VERSION 5.8 ;
BUSBITCHARS "[]" ;
DIVIDERCHAR "/" ;
UNITS
    DATABASE MICRONS 1000 ;
END UNITS

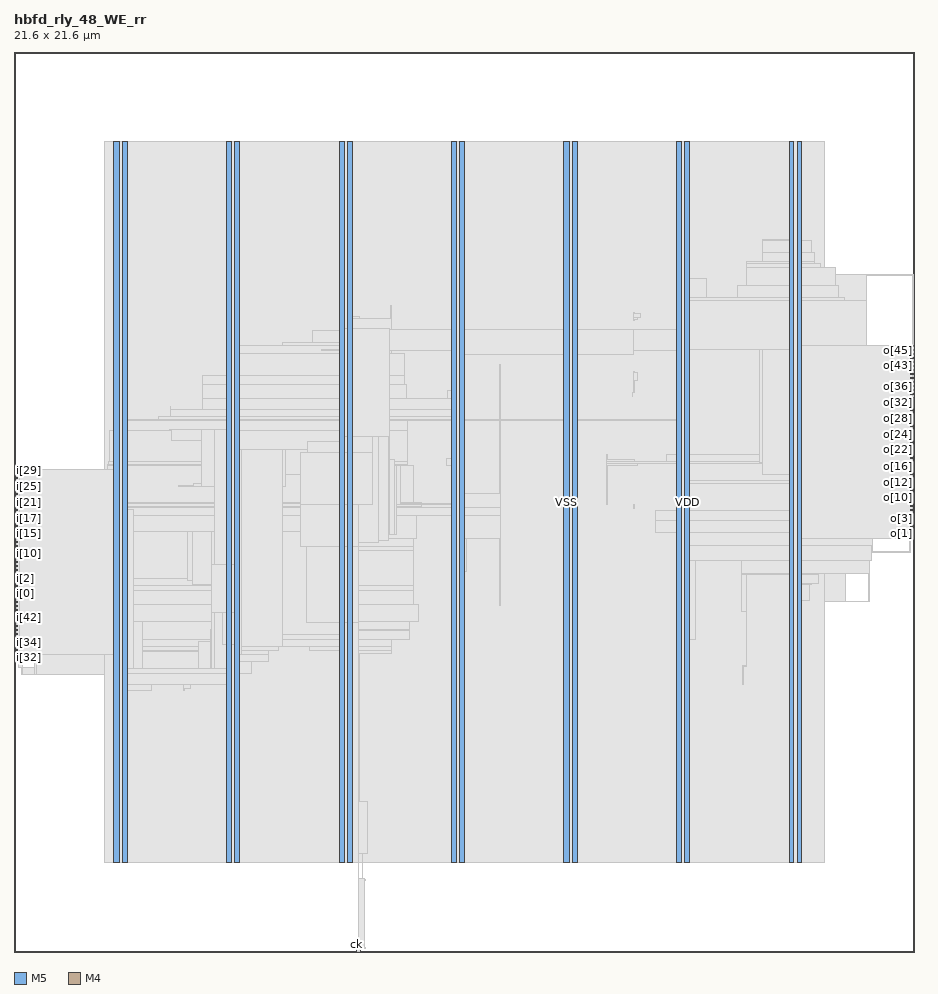
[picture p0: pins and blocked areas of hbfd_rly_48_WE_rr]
MACRO hbfd_rly_48_WE_rr
  FOREIGN hbfd_rly_48_WE_rr 0 0 ;
  CLASS BLOCK ;
  SIZE 21.6 BY 21.6 ;
  PIN ck
    DIRECTION INPUT ;
    USE SIGNAL ;
    PORT
      LAYER M5 ;
        RECT  8.208 0 8.232 0.084 ;
    END
  END ck
  PIN i[0]
    DIRECTION INPUT ;
    USE SIGNAL ;
    PORT
      LAYER M4 ;
        RECT  0 8.592 0.084 8.616 ;
    END
  END i[0]
  PIN i[10]
    DIRECTION INPUT ;
    USE SIGNAL ;
    PORT
      LAYER M4 ;
        RECT  0 9.552 0.084 9.576 ;
    END
  END i[10]
  PIN i[11]
    DIRECTION INPUT ;
    USE SIGNAL ;
    PORT
      LAYER M4 ;
        RECT  0 9.648 0.084 9.672 ;
    END
  END i[11]
  PIN i[12]
    DIRECTION INPUT ;
    USE SIGNAL ;
    PORT
      LAYER M4 ;
        RECT  0 9.744 0.084 9.768 ;
    END
  END i[12]
  PIN i[13]
    DIRECTION INPUT ;
    USE SIGNAL ;
    PORT
      LAYER M4 ;
        RECT  0 9.84 0.084 9.864 ;
    END
  END i[13]
  PIN i[14]
    DIRECTION INPUT ;
    USE SIGNAL ;
    PORT
      LAYER M4 ;
        RECT  0 9.936 0.084 9.96 ;
    END
  END i[14]
  PIN i[15]
    DIRECTION INPUT ;
    USE SIGNAL ;
    PORT
      LAYER M4 ;
        RECT  0 10.032 0.084 10.056 ;
    END
  END i[15]
  PIN i[16]
    DIRECTION INPUT ;
    USE SIGNAL ;
    PORT
      LAYER M4 ;
        RECT  0 10.128 0.084 10.152 ;
    END
  END i[16]
  PIN i[17]
    DIRECTION INPUT ;
    USE SIGNAL ;
    PORT
      LAYER M4 ;
        RECT  0 10.224 0.084 10.248 ;
    END
  END i[17]
  PIN i[18]
    DIRECTION INPUT ;
    USE SIGNAL ;
    PORT
      LAYER M4 ;
        RECT  0 10.32 0.084 10.344 ;
    END
  END i[18]
  PIN i[19]
    DIRECTION INPUT ;
    USE SIGNAL ;
    PORT
      LAYER M4 ;
        RECT  0 10.416 0.084 10.44 ;
    END
  END i[19]
  PIN i[1]
    DIRECTION INPUT ;
    USE SIGNAL ;
    PORT
      LAYER M4 ;
        RECT  0 8.688 0.084 8.712 ;
    END
  END i[1]
  PIN i[20]
    DIRECTION INPUT ;
    USE SIGNAL ;
    PORT
      LAYER M4 ;
        RECT  0 10.512 0.084 10.536 ;
    END
  END i[20]
  PIN i[21]
    DIRECTION INPUT ;
    USE SIGNAL ;
    PORT
      LAYER M4 ;
        RECT  0 10.608 0.084 10.632 ;
    END
  END i[21]
  PIN i[22]
    DIRECTION INPUT ;
    USE SIGNAL ;
    PORT
      LAYER M4 ;
        RECT  0 10.704 0.084 10.728 ;
    END
  END i[22]
  PIN i[23]
    DIRECTION INPUT ;
    USE SIGNAL ;
    PORT
      LAYER M4 ;
        RECT  0 10.8 0.084 10.824 ;
    END
  END i[23]
  PIN i[24]
    DIRECTION INPUT ;
    USE SIGNAL ;
    PORT
      LAYER M4 ;
        RECT  0 10.896 0.084 10.92 ;
    END
  END i[24]
  PIN i[25]
    DIRECTION INPUT ;
    USE SIGNAL ;
    PORT
      LAYER M4 ;
        RECT  0 10.992 0.084 11.016 ;
    END
  END i[25]
  PIN i[26]
    DIRECTION INPUT ;
    USE SIGNAL ;
    PORT
      LAYER M4 ;
        RECT  0 11.088 0.084 11.112 ;
    END
  END i[26]
  PIN i[27]
    DIRECTION INPUT ;
    USE SIGNAL ;
    PORT
      LAYER M4 ;
        RECT  0 11.184 0.084 11.208 ;
    END
  END i[27]
  PIN i[28]
    DIRECTION INPUT ;
    USE SIGNAL ;
    PORT
      LAYER M4 ;
        RECT  0 11.28 0.084 11.304 ;
    END
  END i[28]
  PIN i[29]
    DIRECTION INPUT ;
    USE SIGNAL ;
    PORT
      LAYER M4 ;
        RECT  0 11.376 0.084 11.4 ;
    END
  END i[29]
  PIN i[2]
    DIRECTION INPUT ;
    USE SIGNAL ;
    PORT
      LAYER M4 ;
        RECT  0 8.784 0.084 8.808 ;
    END
  END i[2]
  PIN i[30]
    DIRECTION INPUT ;
    USE SIGNAL ;
    PORT
      LAYER M4 ;
        RECT  0 11.472 0.084 11.496 ;
    END
  END i[30]
  PIN i[31]
    DIRECTION INPUT ;
    USE SIGNAL ;
    PORT
      LAYER M4 ;
        RECT  0 11.568 0.084 11.592 ;
    END
  END i[31]
  PIN i[32]
    DIRECTION INPUT ;
    USE SIGNAL ;
    PORT
      LAYER M4 ;
        RECT  0 7.056 0.084 7.08 ;
    END
  END i[32]
  PIN i[33]
    DIRECTION INPUT ;
    USE SIGNAL ;
    PORT
      LAYER M4 ;
        RECT  0 7.152 0.084 7.176 ;
    END
  END i[33]
  PIN i[34]
    DIRECTION INPUT ;
    USE SIGNAL ;
    PORT
      LAYER M4 ;
        RECT  0 7.248 0.084 7.272 ;
    END
  END i[34]
  PIN i[35]
    DIRECTION INPUT ;
    USE SIGNAL ;
    PORT
      LAYER M4 ;
        RECT  0 7.344 0.084 7.368 ;
    END
  END i[35]
  PIN i[36]
    DIRECTION INPUT ;
    USE SIGNAL ;
    PORT
      LAYER M4 ;
        RECT  0 7.44 0.084 7.464 ;
    END
  END i[36]
  PIN i[37]
    DIRECTION INPUT ;
    USE SIGNAL ;
    PORT
      LAYER M4 ;
        RECT  0 7.536 0.084 7.56 ;
    END
  END i[37]
  PIN i[38]
    DIRECTION INPUT ;
    USE SIGNAL ;
    PORT
      LAYER M4 ;
        RECT  0 7.632 0.084 7.656 ;
    END
  END i[38]
  PIN i[39]
    DIRECTION INPUT ;
    USE SIGNAL ;
    PORT
      LAYER M4 ;
        RECT  0 7.728 0.084 7.752 ;
    END
  END i[39]
  PIN i[3]
    DIRECTION INPUT ;
    USE SIGNAL ;
    PORT
      LAYER M4 ;
        RECT  0 8.88 0.084 8.904 ;
    END
  END i[3]
  PIN i[40]
    DIRECTION INPUT ;
    USE SIGNAL ;
    PORT
      LAYER M4 ;
        RECT  0 7.824 0.084 7.848 ;
    END
  END i[40]
  PIN i[41]
    DIRECTION INPUT ;
    USE SIGNAL ;
    PORT
      LAYER M4 ;
        RECT  0 7.92 0.084 7.944 ;
    END
  END i[41]
  PIN i[42]
    DIRECTION INPUT ;
    USE SIGNAL ;
    PORT
      LAYER M4 ;
        RECT  0 8.016 0.084 8.04 ;
    END
  END i[42]
  PIN i[43]
    DIRECTION INPUT ;
    USE SIGNAL ;
    PORT
      LAYER M4 ;
        RECT  0 8.112 0.084 8.136 ;
    END
  END i[43]
  PIN i[44]
    DIRECTION INPUT ;
    USE SIGNAL ;
    PORT
      LAYER M4 ;
        RECT  0 8.208 0.084 8.232 ;
    END
  END i[44]
  PIN i[45]
    DIRECTION INPUT ;
    USE SIGNAL ;
    PORT
      LAYER M4 ;
        RECT  0 8.304 0.084 8.328 ;
    END
  END i[45]
  PIN i[46]
    DIRECTION INPUT ;
    USE SIGNAL ;
    PORT
      LAYER M4 ;
        RECT  0 8.4 0.084 8.424 ;
    END
  END i[46]
  PIN i[47]
    DIRECTION INPUT ;
    USE SIGNAL ;
    PORT
      LAYER M4 ;
        RECT  0 8.496 0.084 8.52 ;
    END
  END i[47]
  PIN i[4]
    DIRECTION INPUT ;
    USE SIGNAL ;
    PORT
      LAYER M4 ;
        RECT  0 8.976 0.084 9 ;
    END
  END i[4]
  PIN i[5]
    DIRECTION INPUT ;
    USE SIGNAL ;
    PORT
      LAYER M4 ;
        RECT  0 9.072 0.084 9.096 ;
    END
  END i[5]
  PIN i[6]
    DIRECTION INPUT ;
    USE SIGNAL ;
    PORT
      LAYER M4 ;
        RECT  0 9.168 0.084 9.192 ;
    END
  END i[6]
  PIN i[7]
    DIRECTION INPUT ;
    USE SIGNAL ;
    PORT
      LAYER M4 ;
        RECT  0 9.264 0.084 9.288 ;
    END
  END i[7]
  PIN i[8]
    DIRECTION INPUT ;
    USE SIGNAL ;
    PORT
      LAYER M4 ;
        RECT  0 9.36 0.084 9.384 ;
    END
  END i[8]
  PIN i[9]
    DIRECTION INPUT ;
    USE SIGNAL ;
    PORT
      LAYER M4 ;
        RECT  0 9.456 0.084 9.48 ;
    END
  END i[9]
  PIN o[0]
    DIRECTION OUTPUT ;
    USE SIGNAL ;
    PORT
      LAYER M4 ;
        RECT  21.516 9.936 21.6 9.96 ;
    END
  END o[0]
  PIN o[10]
    DIRECTION OUTPUT ;
    USE SIGNAL ;
    PORT
      LAYER M4 ;
        RECT  21.516 10.896 21.6 10.92 ;
    END
  END o[10]
  PIN o[11]
    DIRECTION OUTPUT ;
    USE SIGNAL ;
    PORT
      LAYER M4 ;
        RECT  21.516 10.992 21.6 11.016 ;
    END
  END o[11]
  PIN o[12]
    DIRECTION OUTPUT ;
    USE SIGNAL ;
    PORT
      LAYER M4 ;
        RECT  21.516 11.088 21.6 11.112 ;
    END
  END o[12]
  PIN o[13]
    DIRECTION OUTPUT ;
    USE SIGNAL ;
    PORT
      LAYER M4 ;
        RECT  21.516 11.184 21.6 11.208 ;
    END
  END o[13]
  PIN o[14]
    DIRECTION OUTPUT ;
    USE SIGNAL ;
    PORT
      LAYER M4 ;
        RECT  21.516 11.28 21.6 11.304 ;
    END
  END o[14]
  PIN o[15]
    DIRECTION OUTPUT ;
    USE SIGNAL ;
    PORT
      LAYER M4 ;
        RECT  21.516 11.376 21.6 11.4 ;
    END
  END o[15]
  PIN o[16]
    DIRECTION OUTPUT ;
    USE SIGNAL ;
    PORT
      LAYER M4 ;
        RECT  21.516 11.472 21.6 11.496 ;
    END
  END o[16]
  PIN o[17]
    DIRECTION OUTPUT ;
    USE SIGNAL ;
    PORT
      LAYER M4 ;
        RECT  21.516 11.568 21.6 11.592 ;
    END
  END o[17]
  PIN o[18]
    DIRECTION OUTPUT ;
    USE SIGNAL ;
    PORT
      LAYER M4 ;
        RECT  21.516 11.664 21.6 11.688 ;
    END
  END o[18]
  PIN o[19]
    DIRECTION OUTPUT ;
    USE SIGNAL ;
    PORT
      LAYER M4 ;
        RECT  21.516 11.76 21.6 11.784 ;
    END
  END o[19]
  PIN o[1]
    DIRECTION OUTPUT ;
    USE SIGNAL ;
    PORT
      LAYER M4 ;
        RECT  21.516 10.032 21.6 10.056 ;
    END
  END o[1]
  PIN o[20]
    DIRECTION OUTPUT ;
    USE SIGNAL ;
    PORT
      LAYER M4 ;
        RECT  21.516 11.856 21.6 11.88 ;
    END
  END o[20]
  PIN o[21]
    DIRECTION OUTPUT ;
    USE SIGNAL ;
    PORT
      LAYER M4 ;
        RECT  21.516 11.952 21.6 11.976 ;
    END
  END o[21]
  PIN o[22]
    DIRECTION OUTPUT ;
    USE SIGNAL ;
    PORT
      LAYER M4 ;
        RECT  21.516 12.048 21.6 12.072 ;
    END
  END o[22]
  PIN o[23]
    DIRECTION OUTPUT ;
    USE SIGNAL ;
    PORT
      LAYER M4 ;
        RECT  21.516 12.144 21.6 12.168 ;
    END
  END o[23]
  PIN o[24]
    DIRECTION OUTPUT ;
    USE SIGNAL ;
    PORT
      LAYER M4 ;
        RECT  21.516 12.24 21.6 12.264 ;
    END
  END o[24]
  PIN o[25]
    DIRECTION OUTPUT ;
    USE SIGNAL ;
    PORT
      LAYER M4 ;
        RECT  21.516 12.336 21.6 12.36 ;
    END
  END o[25]
  PIN o[26]
    DIRECTION OUTPUT ;
    USE SIGNAL ;
    PORT
      LAYER M4 ;
        RECT  21.516 12.432 21.6 12.456 ;
    END
  END o[26]
  PIN o[27]
    DIRECTION OUTPUT ;
    USE SIGNAL ;
    PORT
      LAYER M4 ;
        RECT  21.516 12.528 21.6 12.552 ;
    END
  END o[27]
  PIN o[28]
    DIRECTION OUTPUT ;
    USE SIGNAL ;
    PORT
      LAYER M4 ;
        RECT  21.516 12.624 21.6 12.648 ;
    END
  END o[28]
  PIN o[29]
    DIRECTION OUTPUT ;
    USE SIGNAL ;
    PORT
      LAYER M4 ;
        RECT  21.516 12.72 21.6 12.744 ;
    END
  END o[29]
  PIN o[2]
    DIRECTION OUTPUT ;
    USE SIGNAL ;
    PORT
      LAYER M4 ;
        RECT  21.516 10.128 21.6 10.152 ;
    END
  END o[2]
  PIN o[30]
    DIRECTION OUTPUT ;
    USE SIGNAL ;
    PORT
      LAYER M4 ;
        RECT  21.516 12.816 21.6 12.84 ;
    END
  END o[30]
  PIN o[31]
    DIRECTION OUTPUT ;
    USE SIGNAL ;
    PORT
      LAYER M4 ;
        RECT  21.516 12.912 21.6 12.936 ;
    END
  END o[31]
  PIN o[32]
    DIRECTION OUTPUT ;
    USE SIGNAL ;
    PORT
      LAYER M4 ;
        RECT  21.516 13.008 21.6 13.032 ;
    END
  END o[32]
  PIN o[33]
    DIRECTION OUTPUT ;
    USE SIGNAL ;
    PORT
      LAYER M4 ;
        RECT  21.516 13.104 21.6 13.128 ;
    END
  END o[33]
  PIN o[34]
    DIRECTION OUTPUT ;
    USE SIGNAL ;
    PORT
      LAYER M4 ;
        RECT  21.516 13.2 21.6 13.224 ;
    END
  END o[34]
  PIN o[35]
    DIRECTION OUTPUT ;
    USE SIGNAL ;
    PORT
      LAYER M4 ;
        RECT  21.516 13.296 21.6 13.32 ;
    END
  END o[35]
  PIN o[36]
    DIRECTION OUTPUT ;
    USE SIGNAL ;
    PORT
      LAYER M4 ;
        RECT  21.516 13.392 21.6 13.416 ;
    END
  END o[36]
  PIN o[37]
    DIRECTION OUTPUT ;
    USE SIGNAL ;
    PORT
      LAYER M4 ;
        RECT  21.516 13.488 21.6 13.512 ;
    END
  END o[37]
  PIN o[38]
    DIRECTION OUTPUT ;
    USE SIGNAL ;
    PORT
      LAYER M4 ;
        RECT  21.516 13.584 21.6 13.608 ;
    END
  END o[38]
  PIN o[39]
    DIRECTION OUTPUT ;
    USE SIGNAL ;
    PORT
      LAYER M4 ;
        RECT  21.516 13.68 21.6 13.704 ;
    END
  END o[39]
  PIN o[3]
    DIRECTION OUTPUT ;
    USE SIGNAL ;
    PORT
      LAYER M4 ;
        RECT  21.516 10.224 21.6 10.248 ;
    END
  END o[3]
  PIN o[40]
    DIRECTION OUTPUT ;
    USE SIGNAL ;
    PORT
      LAYER M4 ;
        RECT  21.516 13.776 21.6 13.8 ;
    END
  END o[40]
  PIN o[41]
    DIRECTION OUTPUT ;
    USE SIGNAL ;
    PORT
      LAYER M4 ;
        RECT  21.516 13.872 21.6 13.896 ;
    END
  END o[41]
  PIN o[42]
    DIRECTION OUTPUT ;
    USE SIGNAL ;
    PORT
      LAYER M4 ;
        RECT  21.516 13.968 21.6 13.992 ;
    END
  END o[42]
  PIN o[43]
    DIRECTION OUTPUT ;
    USE SIGNAL ;
    PORT
      LAYER M4 ;
        RECT  21.516 14.064 21.6 14.088 ;
    END
  END o[43]
  PIN o[44]
    DIRECTION OUTPUT ;
    USE SIGNAL ;
    PORT
      LAYER M4 ;
        RECT  21.516 14.16 21.6 14.184 ;
    END
  END o[44]
  PIN o[45]
    DIRECTION OUTPUT ;
    USE SIGNAL ;
    PORT
      LAYER M4 ;
        RECT  21.516 14.256 21.6 14.28 ;
    END
  END o[45]
  PIN o[46]
    DIRECTION OUTPUT ;
    USE SIGNAL ;
    PORT
      LAYER M4 ;
        RECT  21.516 14.352 21.6 14.376 ;
    END
  END o[46]
  PIN o[47]
    DIRECTION OUTPUT ;
    USE SIGNAL ;
    PORT
      LAYER M4 ;
        RECT  21.516 14.448 21.6 14.472 ;
    END
  END o[47]
  PIN o[4]
    DIRECTION OUTPUT ;
    USE SIGNAL ;
    PORT
      LAYER M4 ;
        RECT  21.516 10.32 21.6 10.344 ;
    END
  END o[4]
  PIN o[5]
    DIRECTION OUTPUT ;
    USE SIGNAL ;
    PORT
      LAYER M4 ;
        RECT  21.516 10.416 21.6 10.44 ;
    END
  END o[5]
  PIN o[6]
    DIRECTION OUTPUT ;
    USE SIGNAL ;
    PORT
      LAYER M4 ;
        RECT  21.516 10.512 21.6 10.536 ;
    END
  END o[6]
  PIN o[7]
    DIRECTION OUTPUT ;
    USE SIGNAL ;
    PORT
      LAYER M4 ;
        RECT  21.516 10.608 21.6 10.632 ;
    END
  END o[7]
  PIN o[8]
    DIRECTION OUTPUT ;
    USE SIGNAL ;
    PORT
      LAYER M4 ;
        RECT  21.516 10.704 21.6 10.728 ;
    END
  END o[8]
  PIN o[9]
    DIRECTION OUTPUT ;
    USE SIGNAL ;
    PORT
      LAYER M4 ;
        RECT  21.516 10.8 21.6 10.824 ;
    END
  END o[9]
  PIN rs
    DIRECTION INPUT ;
    USE SIGNAL ;
    PORT
      LAYER M5 ;
        RECT  8.304 0 8.328 0.084 ;
    END
  END rs
  PIN rso
    DIRECTION OUTPUT ;
    USE SIGNAL ;
    PORT
      LAYER M4 ;
        RECT  21.516 14.544 21.6 14.568 ;
    END
  END rso
  PIN VDD
    DIRECTION INOUT ;
    USE POWER ;
    PORT
      LAYER M5 ;
        RECT  18.792 2.151 18.912 19.449 ;
        RECT  16.092 2.151 16.212 19.449 ;
        RECT  13.392 2.151 13.512 19.449 ;
        RECT  10.692 2.151 10.812 19.449 ;
        RECT  7.992 2.151 8.112 19.449 ;
        RECT  5.292 2.151 5.412 19.449 ;
        RECT  2.592 2.151 2.712 19.449 ;
    END
  END VDD
  PIN VSS
    DIRECTION INOUT ;
    USE GROUND ;
    PORT
      LAYER M5 ;
        RECT  18.6 2.137 18.72 19.463 ;
        RECT  15.9 2.137 16.02 19.463 ;
        RECT  13.2 2.137 13.32 19.463 ;
        RECT  10.5 2.137 10.62 19.463 ;
        RECT  7.8 2.137 7.92 19.463 ;
        RECT  5.1 2.137 5.22 19.463 ;
        RECT  2.4 2.137 2.52 19.463 ;
    END
  END VSS
  OBS
    LAYER RVTN ;
     RECT  2.16 2.16 19.44 2.295 ;
     RECT  2.16 2.565 19.44 2.835 ;
     RECT  2.16 3.105 19.44 3.375 ;
     RECT  2.16 3.645 19.44 3.915 ;
     RECT  2.16 4.185 19.44 4.455 ;
     RECT  2.16 4.725 19.44 4.995 ;
     RECT  2.16 5.265 19.44 5.535 ;
     RECT  2.16 5.805 19.44 6.075 ;
     RECT  2.16 6.345 19.44 6.615 ;
     RECT  2.16 6.885 19.44 7.155 ;
     RECT  2.16 7.425 19.44 7.695 ;
     RECT  2.16 7.965 19.44 8.235 ;
     RECT  2.16 8.505 19.44 8.775 ;
     RECT  2.16 9.045 19.44 9.315 ;
     RECT  2.16 9.585 19.44 9.855 ;
     RECT  2.16 10.125 19.44 10.395 ;
     RECT  2.16 10.665 19.44 10.935 ;
     RECT  2.16 11.205 19.44 11.475 ;
     RECT  2.16 11.745 19.44 12.015 ;
     RECT  2.16 12.285 19.44 12.555 ;
     RECT  2.16 12.825 19.44 13.095 ;
     RECT  2.16 13.365 19.44 13.635 ;
     RECT  2.16 13.905 19.44 14.175 ;
     RECT  2.16 14.445 19.44 14.715 ;
     RECT  2.16 14.985 19.44 15.255 ;
     RECT  2.16 15.525 19.44 15.795 ;
     RECT  2.16 16.065 19.44 16.335 ;
     RECT  2.16 16.605 19.44 16.875 ;
     RECT  2.16 17.145 19.44 17.415 ;
     RECT  2.16 17.685 19.44 17.955 ;
     RECT  2.16 18.225 19.44 18.495 ;
     RECT  2.16 18.765 19.44 19.035 ;
     RECT  2.16 19.305 19.44 19.44 ;
    LAYER RVTP ;
     RECT  2.16 2.295 19.44 2.565 ;
     RECT  2.16 2.835 19.44 3.105 ;
     RECT  2.16 3.375 19.44 3.645 ;
     RECT  2.16 3.915 19.44 4.185 ;
     RECT  2.16 4.455 19.44 4.725 ;
     RECT  2.16 4.995 19.44 5.265 ;
     RECT  2.16 5.535 19.44 5.805 ;
     RECT  2.16 6.075 19.44 6.345 ;
     RECT  2.16 6.615 19.44 6.885 ;
     RECT  2.16 7.155 19.44 7.425 ;
     RECT  2.16 7.695 19.44 7.965 ;
     RECT  2.16 8.235 19.44 8.505 ;
     RECT  2.16 8.775 19.44 9.045 ;
     RECT  2.16 9.315 19.44 9.585 ;
     RECT  2.16 9.855 19.44 10.125 ;
     RECT  2.16 10.395 19.44 10.665 ;
     RECT  2.16 10.935 19.44 11.205 ;
     RECT  2.16 11.475 19.44 11.745 ;
     RECT  2.16 12.015 19.44 12.285 ;
     RECT  2.16 12.555 19.44 12.825 ;
     RECT  2.16 13.095 19.44 13.365 ;
     RECT  2.16 13.635 19.44 13.905 ;
     RECT  2.16 14.175 19.44 14.445 ;
     RECT  2.16 14.715 19.44 14.985 ;
     RECT  2.16 15.255 19.44 15.525 ;
     RECT  2.16 15.795 19.44 16.065 ;
     RECT  2.16 16.335 19.44 16.605 ;
     RECT  2.16 16.875 19.44 17.145 ;
     RECT  2.16 17.415 19.44 17.685 ;
     RECT  2.16 17.955 19.44 18.225 ;
     RECT  2.16 18.495 19.44 18.765 ;
     RECT  2.16 19.035 19.44 19.305 ;
    LAYER M1 ;
     RECT  2.16 2.151 19.44 19.449 ;
    LAYER M2 ;
     RECT  0.103 6.822 0.175 6.84 ;
     RECT  0.175 6.66 0.499 6.84 ;
     RECT  0.499 6.66 0.535 7.11 ;
     RECT  0.535 6.66 2.16 7.254 ;
     RECT  2.155 10.746 2.16 10.764 ;
     RECT  2.16 2.151 19.44 19.449 ;
     RECT  19.44 15.606 19.715 16.434 ;
     RECT  19.44 10.746 19.931 14.508 ;
     RECT  19.44 8.406 19.967 9.774 ;
     RECT  19.967 9.36 20.003 9.774 ;
     RECT  19.715 15.606 20.471 16.254 ;
     RECT  19.931 14.418 20.507 14.508 ;
     RECT  19.967 8.406 20.543 8.424 ;
     RECT  19.931 11.214 20.543 13.464 ;
     RECT  20.003 9.396 20.579 9.774 ;
     RECT  20.579 9.594 20.615 9.774 ;
     RECT  20.543 11.25 20.615 11.808 ;
     RECT  20.543 12.6 21.479 13.464 ;
     RECT  20.615 9.594 21.515 9.612 ;
     RECT  20.615 11.79 21.515 11.808 ;
     RECT  21.479 12.6 21.515 13.32 ;
     RECT  20.507 14.49 21.515 14.508 ;
     RECT  21.515 13.302 21.587 13.32 ;
     RECT  20.471 16.236 21.587 16.254 ;
    LAYER M3 ;
     RECT  8.352 1.723 8.37 2.143 ;
     RECT  7.815 2.143 8.37 2.371 ;
     RECT  2.415 2.143 2.505 2.413 ;
     RECT  5.115 2.143 5.205 2.413 ;
     RECT  10.515 2.143 10.605 2.413 ;
     RECT  13.215 2.143 13.305 2.413 ;
     RECT  15.915 2.143 16.005 2.413 ;
     RECT  18.615 2.143 18.705 2.413 ;
     RECT  7.815 2.371 8.478 3.605 ;
     RECT  2.415 2.413 2.697 6.277 ;
     RECT  4.068 6.277 4.086 6.313 ;
     RECT  2.415 6.277 3.294 6.421 ;
     RECT  4.068 6.313 4.23 6.421 ;
     RECT  5.115 2.413 5.397 6.421 ;
     RECT  2.415 6.421 5.397 6.691 ;
     RECT  0.18 6.655 0.198 6.817 ;
     RECT  17.496 6.421 17.514 6.853 ;
     RECT  17.496 6.853 17.586 6.881 ;
     RECT  2.415 6.691 5.706 6.961 ;
     RECT  0.108 6.817 0.198 7.085 ;
     RECT  0.18 7.085 0.198 7.087 ;
     RECT  2.415 6.961 6.102 7.147 ;
     RECT  7.815 3.605 8.298 7.159 ;
     RECT  0.18 7.087 0.522 7.231 ;
     RECT  2.34 7.147 6.102 7.231 ;
     RECT  7.815 7.159 9.054 7.231 ;
     RECT  2.34 7.231 6.354 7.321 ;
     RECT  7.092 7.231 9.054 7.321 ;
     RECT  2.34 7.321 9.054 7.339 ;
     RECT  2.304 7.339 9.054 7.501 ;
     RECT  15.915 2.413 16.197 7.501 ;
     RECT  0.18 7.231 0.558 7.565 ;
     RECT  0.18 7.565 0.522 7.661 ;
     RECT  0.18 7.661 0.198 7.853 ;
     RECT  2.304 7.501 9.486 7.933 ;
     RECT  17.568 6.881 17.586 8.167 ;
     RECT  2.304 7.933 9.702 8.339 ;
     RECT  18.615 2.413 18.897 8.437 ;
     RECT  2.304 8.339 9.594 8.683 ;
     RECT  2.268 8.683 9.594 8.807 ;
     RECT  18.615 8.437 19.098 8.815 ;
     RECT  18.615 8.815 19.134 8.851 ;
     RECT  17.46 8.167 17.586 9.049 ;
     RECT  18.615 8.851 19.314 9.049 ;
     RECT  17.46 9.049 19.314 9.085 ;
     RECT  20.52 8.401 20.538 9.085 ;
     RECT  10.515 2.413 10.797 9.121 ;
     RECT  15.915 7.501 16.362 9.391 ;
     RECT  17.46 9.085 20.538 9.391 ;
     RECT  2.304 8.807 9.594 9.643 ;
     RECT  2.268 9.643 9.594 9.739 ;
     RECT  15.915 9.391 20.574 9.751 ;
     RECT  2.232 9.739 9.594 9.931 ;
     RECT  10.515 9.121 10.854 9.931 ;
     RECT  11.664 8.311 11.682 9.931 ;
     RECT  15.915 9.751 20.61 10.057 ;
     RECT  21.492 9.589 21.51 10.157 ;
     RECT  15.408 10.057 20.61 10.349 ;
     RECT  2.232 9.931 9.666 10.471 ;
     RECT  10.515 9.931 11.682 10.471 ;
     RECT  0.144 10.075 0.162 10.507 ;
     RECT  15.408 10.349 20.574 10.589 ;
     RECT  0.144 10.507 0.342 10.637 ;
     RECT  2.232 10.471 11.682 10.661 ;
     RECT  2.232 10.661 9.774 10.699 ;
     RECT  14.868 10.633 14.886 10.733 ;
     RECT  2.16 10.699 9.774 10.769 ;
     RECT  2.232 10.769 9.774 10.781 ;
     RECT  10.515 10.661 11.682 11.003 ;
     RECT  15.915 10.589 20.574 11.245 ;
     RECT  15.915 11.245 20.61 11.309 ;
     RECT  10.515 11.003 10.818 11.399 ;
     RECT  19.944 11.309 20.61 11.501 ;
     RECT  19.944 11.501 20.574 11.597 ;
     RECT  2.232 10.781 9.594 11.669 ;
     RECT  10.515 11.399 10.797 11.677 ;
     RECT  14.22 10.741 14.238 11.677 ;
     RECT  2.232 11.669 9.45 11.705 ;
     RECT  14.22 11.677 14.958 11.713 ;
     RECT  15.915 11.309 19.206 11.713 ;
     RECT  2.268 11.705 9.45 11.777 ;
     RECT  14.22 11.713 19.206 11.777 ;
     RECT  14.22 11.777 14.886 11.813 ;
     RECT  10.368 11.677 10.797 11.849 ;
     RECT  14.22 11.813 14.238 11.939 ;
     RECT  15.66 11.777 19.206 11.939 ;
     RECT  19.944 11.597 20.538 12.173 ;
     RECT  19.944 12.173 20.502 12.269 ;
     RECT  15.915 11.939 19.206 12.479 ;
     RECT  2.304 11.777 9.45 12.515 ;
     RECT  21.492 11.659 21.51 12.523 ;
     RECT  21.456 12.523 21.51 12.715 ;
     RECT  2.415 12.515 9.45 12.757 ;
     RECT  10.515 11.849 10.797 12.757 ;
     RECT  2.415 12.757 10.797 12.785 ;
     RECT  21.312 12.715 21.51 12.845 ;
     RECT  3.456 12.785 10.797 12.857 ;
     RECT  3.744 12.857 10.797 13.019 ;
     RECT  3.744 13.019 3.762 13.091 ;
     RECT  20.484 12.269 20.502 13.195 ;
     RECT  4.536 13.019 10.797 13.289 ;
     RECT  20.448 13.195 20.502 13.289 ;
     RECT  21.42 12.845 21.51 13.297 ;
     RECT  15.915 12.479 19.026 13.369 ;
     RECT  14.832 13.333 14.85 13.432 ;
     RECT  14.832 13.432 14.886 13.433 ;
     RECT  21.42 13.297 21.582 13.433 ;
     RECT  10.404 13.289 10.797 13.469 ;
     RECT  21.456 13.433 21.582 13.469 ;
     RECT  20.448 13.289 20.466 13.483 ;
     RECT  4.536 13.289 9.414 13.631 ;
     RECT  14.868 13.433 14.886 13.711 ;
     RECT  15.915 13.369 19.098 13.771 ;
     RECT  4.536 13.631 9.378 13.829 ;
     RECT  14.868 13.711 14.958 13.901 ;
     RECT  14.868 13.901 14.886 13.937 ;
     RECT  15.915 13.771 19.134 14.059 ;
     RECT  19.908 13.483 20.466 14.059 ;
     RECT  11.664 11.003 11.682 14.099 ;
     RECT  15.915 14.059 20.466 14.347 ;
     RECT  5.115 13.829 9.378 14.369 ;
     RECT  15.915 14.347 20.502 14.441 ;
     RECT  21.492 13.469 21.582 14.513 ;
     RECT  5.115 14.369 9.054 14.549 ;
     RECT  6.444 14.549 9.054 14.639 ;
     RECT  14.832 14.347 14.85 14.819 ;
     RECT  7.164 14.639 9.054 14.909 ;
     RECT  14.868 15.151 14.886 15.187 ;
     RECT  7.815 14.909 9.054 15.215 ;
     RECT  14.868 15.187 14.958 15.223 ;
     RECT  7.815 15.215 8.298 15.251 ;
     RECT  14.868 15.223 15.03 15.323 ;
     RECT  14.868 15.323 14.886 15.359 ;
     RECT  9.036 15.215 9.054 15.521 ;
     RECT  15.915 14.441 20.466 15.629 ;
     RECT  15.915 15.629 19.926 15.719 ;
     RECT  17.352 15.719 19.782 15.989 ;
     RECT  15.915 15.719 16.614 16.169 ;
     RECT  21.564 14.513 21.582 16.259 ;
     RECT  17.568 15.989 19.71 16.439 ;
     RECT  17.568 16.439 19.35 16.529 ;
     RECT  17.568 16.529 19.206 16.565 ;
     RECT  17.964 16.565 19.206 16.799 ;
     RECT  17.964 16.799 19.134 17.069 ;
     RECT  17.964 17.069 18.897 17.105 ;
     RECT  2.415 12.785 2.697 19.187 ;
     RECT  5.115 14.549 5.397 19.187 ;
     RECT  7.815 15.251 8.097 19.187 ;
     RECT  10.515 13.469 10.797 19.187 ;
     RECT  13.215 2.413 13.497 19.187 ;
     RECT  15.915 16.169 16.197 19.187 ;
     RECT  18.615 17.105 18.897 19.187 ;
     RECT  2.415 19.187 2.505 19.457 ;
     RECT  5.115 19.187 5.205 19.457 ;
     RECT  7.815 19.187 7.905 19.457 ;
     RECT  10.515 19.187 10.605 19.457 ;
     RECT  13.215 19.187 13.305 19.457 ;
     RECT  15.915 19.187 16.005 19.457 ;
     RECT  18.615 19.187 18.705 19.457 ;
    LAYER M4 ;
     RECT  0.06 7.056 0.137 11.592 ;
     RECT  0.137 7.152 2.408 11.592 ;
     RECT  2.408 2.148 2.512 19.452 ;
     RECT  2.512 2.418 2.704 19.182 ;
     RECT  2.704 6.816 2.873 10.632 ;
     RECT  2.873 6.816 3.089 7.944 ;
     RECT  3.733 12.528 3.769 12.552 ;
     RECT  2.873 8.976 4.165 10.104 ;
     RECT  4.165 8.928 4.273 10.104 ;
     RECT  3.949 11.184 4.309 11.208 ;
     RECT  3.089 6.816 4.417 7.224 ;
     RECT  4.309 11.184 4.489 11.256 ;
     RECT  3.769 12.288 4.489 12.552 ;
     RECT  4.417 6.816 4.705 7.464 ;
     RECT  4.705 6.816 4.741 7.752 ;
     RECT  4.273 8.832 4.741 10.104 ;
     RECT  4.741 6.816 4.813 10.104 ;
     RECT  4.489 11.184 4.813 12.552 ;
     RECT  4.813 6.816 5.108 12.552 ;
     RECT  5.108 2.148 5.212 19.452 ;
     RECT  5.212 2.418 5.404 19.182 ;
     RECT  5.404 7.152 5.465 12.072 ;
     RECT  5.465 7.344 6.437 12.072 ;
     RECT  6.437 11.184 6.509 12.072 ;
     RECT  6.509 11.472 7.045 12.072 ;
     RECT  6.437 7.632 7.808 10.104 ;
     RECT  7.045 11.472 7.808 12.264 ;
     RECT  7.369 14.448 7.808 14.472 ;
     RECT  7.808 2.148 7.912 19.452 ;
     RECT  7.912 2.148 8.104 19.182 ;
     RECT  8.104 7.632 8.165 12.408 ;
     RECT  8.165 7.632 8.273 8.232 ;
     RECT  8.165 9.552 8.273 12.408 ;
     RECT  8.101 0.096 8.291 0.216 ;
     RECT  8.291 0.096 8.435 0.12 ;
     RECT  8.341 1.728 8.435 1.752 ;
     RECT  8.273 9.84 8.741 12.408 ;
     RECT  8.741 9.888 8.993 12.408 ;
     RECT  8.993 10.032 9.011 12.408 ;
     RECT  9.011 10.032 9.137 11.832 ;
     RECT  9.137 10.032 9.173 11.688 ;
     RECT  9.173 10.752 9.281 11.688 ;
     RECT  8.273 7.728 9.497 7.752 ;
     RECT  9.281 10.752 10.508 10.776 ;
     RECT  10.105 12.768 10.508 12.792 ;
     RECT  8.104 14.448 10.508 14.952 ;
     RECT  10.508 2.148 10.612 19.452 ;
     RECT  10.612 2.418 10.804 19.182 ;
     RECT  10.804 12.768 13.208 12.792 ;
     RECT  10.804 14.352 13.208 14.952 ;
     RECT  13.208 2.148 13.312 19.452 ;
     RECT  13.312 2.418 13.504 19.182 ;
     RECT  13.504 14.352 14.861 14.952 ;
     RECT  13.504 12.768 15.908 12.792 ;
     RECT  14.861 14.448 15.908 14.952 ;
     RECT  15.908 2.148 16.012 19.452 ;
     RECT  16.012 2.418 16.204 19.182 ;
     RECT  16.204 11.952 17.881 14.472 ;
     RECT  17.881 11.76 17.953 14.472 ;
     RECT  17.953 11.472 18.608 14.472 ;
     RECT  18.608 2.148 18.712 19.452 ;
     RECT  18.712 2.418 18.904 19.182 ;
     RECT  18.904 9.936 21.564 14.568 ;
    LAYER M5 ;
     RECT  8.208 0.016 8.328 0.085 ;
     RECT  8.112 0.085 8.424 0.227 ;
     RECT  8.256 0.227 8.424 1.763 ;
     RECT  8.256 1.763 8.28 2.137 ;
     RECT  2.4 2.137 2.52 2.151 ;
     RECT  5.1 2.137 5.22 2.151 ;
     RECT  10.5 2.137 10.62 2.151 ;
     RECT  13.2 2.137 13.32 2.151 ;
     RECT  15.9 2.137 16.02 2.151 ;
     RECT  18.6 2.137 18.72 2.151 ;
     RECT  5.1 2.151 5.412 7.381 ;
     RECT  7.8 2.137 8.28 7.909 ;
     RECT  4.992 7.381 5.412 8.149 ;
     RECT  4.752 8.149 5.412 9.299 ;
     RECT  7.008 7.909 8.28 9.733 ;
     RECT  6.864 9.733 8.28 10.741 ;
     RECT  6.864 10.741 8.616 11.987 ;
     RECT  7.8 11.987 8.616 12.373 ;
     RECT  7.8 12.373 9 14.963 ;
     RECT  2.4 2.151 2.712 19.449 ;
     RECT  5.1 9.299 5.412 19.449 ;
     RECT  7.8 14.963 8.112 19.449 ;
     RECT  10.5 2.151 10.812 19.449 ;
     RECT  13.2 2.151 13.512 19.449 ;
     RECT  15.9 2.151 16.212 19.449 ;
     RECT  18.6 2.151 18.912 19.449 ;
     RECT  2.4 19.449 2.52 19.463 ;
     RECT  5.1 19.449 5.22 19.463 ;
     RECT  7.8 19.449 7.92 19.463 ;
     RECT  10.5 19.449 10.62 19.463 ;
     RECT  13.2 19.449 13.32 19.463 ;
     RECT  15.9 19.449 16.02 19.463 ;
     RECT  18.6 19.449 18.72 19.463 ;
  END
END hbfd_rly_48_WE_rr
END LIBRARY
